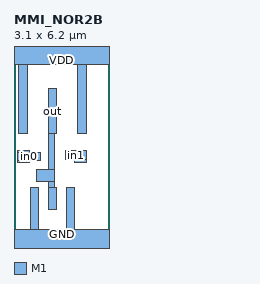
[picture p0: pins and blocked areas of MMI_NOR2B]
MACRO MMI_NOR2B
	CLASS CORE ;
	FOREIGN MMI_NOR2B 0 0 ;
	SIZE 3.1 BY 6.2 ;
	SYMMETRY X Y ;
	SITE CORE1 ;
	PIN out
		DIRECTION output ;
		USE SIGNAL ;
		PORT
			LAYER M1 ;
			RECT 1.12 3.53 1.4 5 ;
			LAYER M1 ;
			RECT 1.125 2.36 1.32 3.53 ;
			LAYER M1 ;
			RECT 0.74 1.98 1.32 2.36 ;
			LAYER M1 ;
			RECT 1.125 1.765 1.32 1.98 ;
			LAYER M1 ;
			RECT 1.12 1.065 1.4 1.765 ;
		END
		AntennaDiffArea 1.0164 ;
	END out
	PIN in1
		DIRECTION input ;
		USE SIGNAL ;
		PORT
			LAYER M1 ;
			RECT 1.98 2.975 2.36 2.98 ;
			LAYER M1 ;
			RECT 1.96 2.97 2.36 2.975 ;
			LAYER M1 ;
			RECT 1.68 2.69 2.36 2.97 ;
			LAYER M1 ;
			RECT 1.98 2.6 2.36 2.69 ;
		END
		AntennaGateArea 0.5775 ;
	END in1
	PIN GND
		DIRECTION inout ;
		USE GROUND ;
		PORT
			LAYER M1 ;
			RECT 0.53 0.42 0.81 1.765 ;
			LAYER M1 ;
			RECT 1.71 0.42 1.99 1.765 ;
			LAYER M1 ;
			RECT 0 -0.42 3.1 0.42 ;
		END
	END GND
	PIN VDD
		DIRECTION inout ;
		USE POWER ;
		PORT
			LAYER M1 ;
			RECT 0 5.78 3.1 6.62 ;
			LAYER M1 ;
			RECT 0.16 3.53 0.44 5.78 ;
			LAYER M1 ;
			RECT 2.08 3.53 2.36 5.78 ;
		END
	END VDD
	PIN in0
		DIRECTION input ;
		USE SIGNAL ;
		PORT
			LAYER M1 ;
			RECT 0.12 2.935 0.5 2.98 ;
			LAYER M1 ;
			RECT 0.12 2.93 0.595 2.935 ;
			LAYER M1 ;
			RECT 0.12 2.65 0.875 2.93 ;
			LAYER M1 ;
			RECT 0.12 2.6 0.5 2.65 ;
		END
		AntennaGateArea 0.5775 ;
	END in0
	OBS
	END
END MMI_NOR2B
